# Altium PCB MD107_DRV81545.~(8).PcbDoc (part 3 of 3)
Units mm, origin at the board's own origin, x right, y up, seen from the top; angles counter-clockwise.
Board outline 152.45 x 74.46 mm, 4 copper layers (Top Layer, Mid-Layer 1, Mid-Layer 2, Bottom Layer), stack 2.355 mm thick; 223 components, 122 nets, 703 pads, 225 vias.
Unrouted connection lines stored in the file: 85.

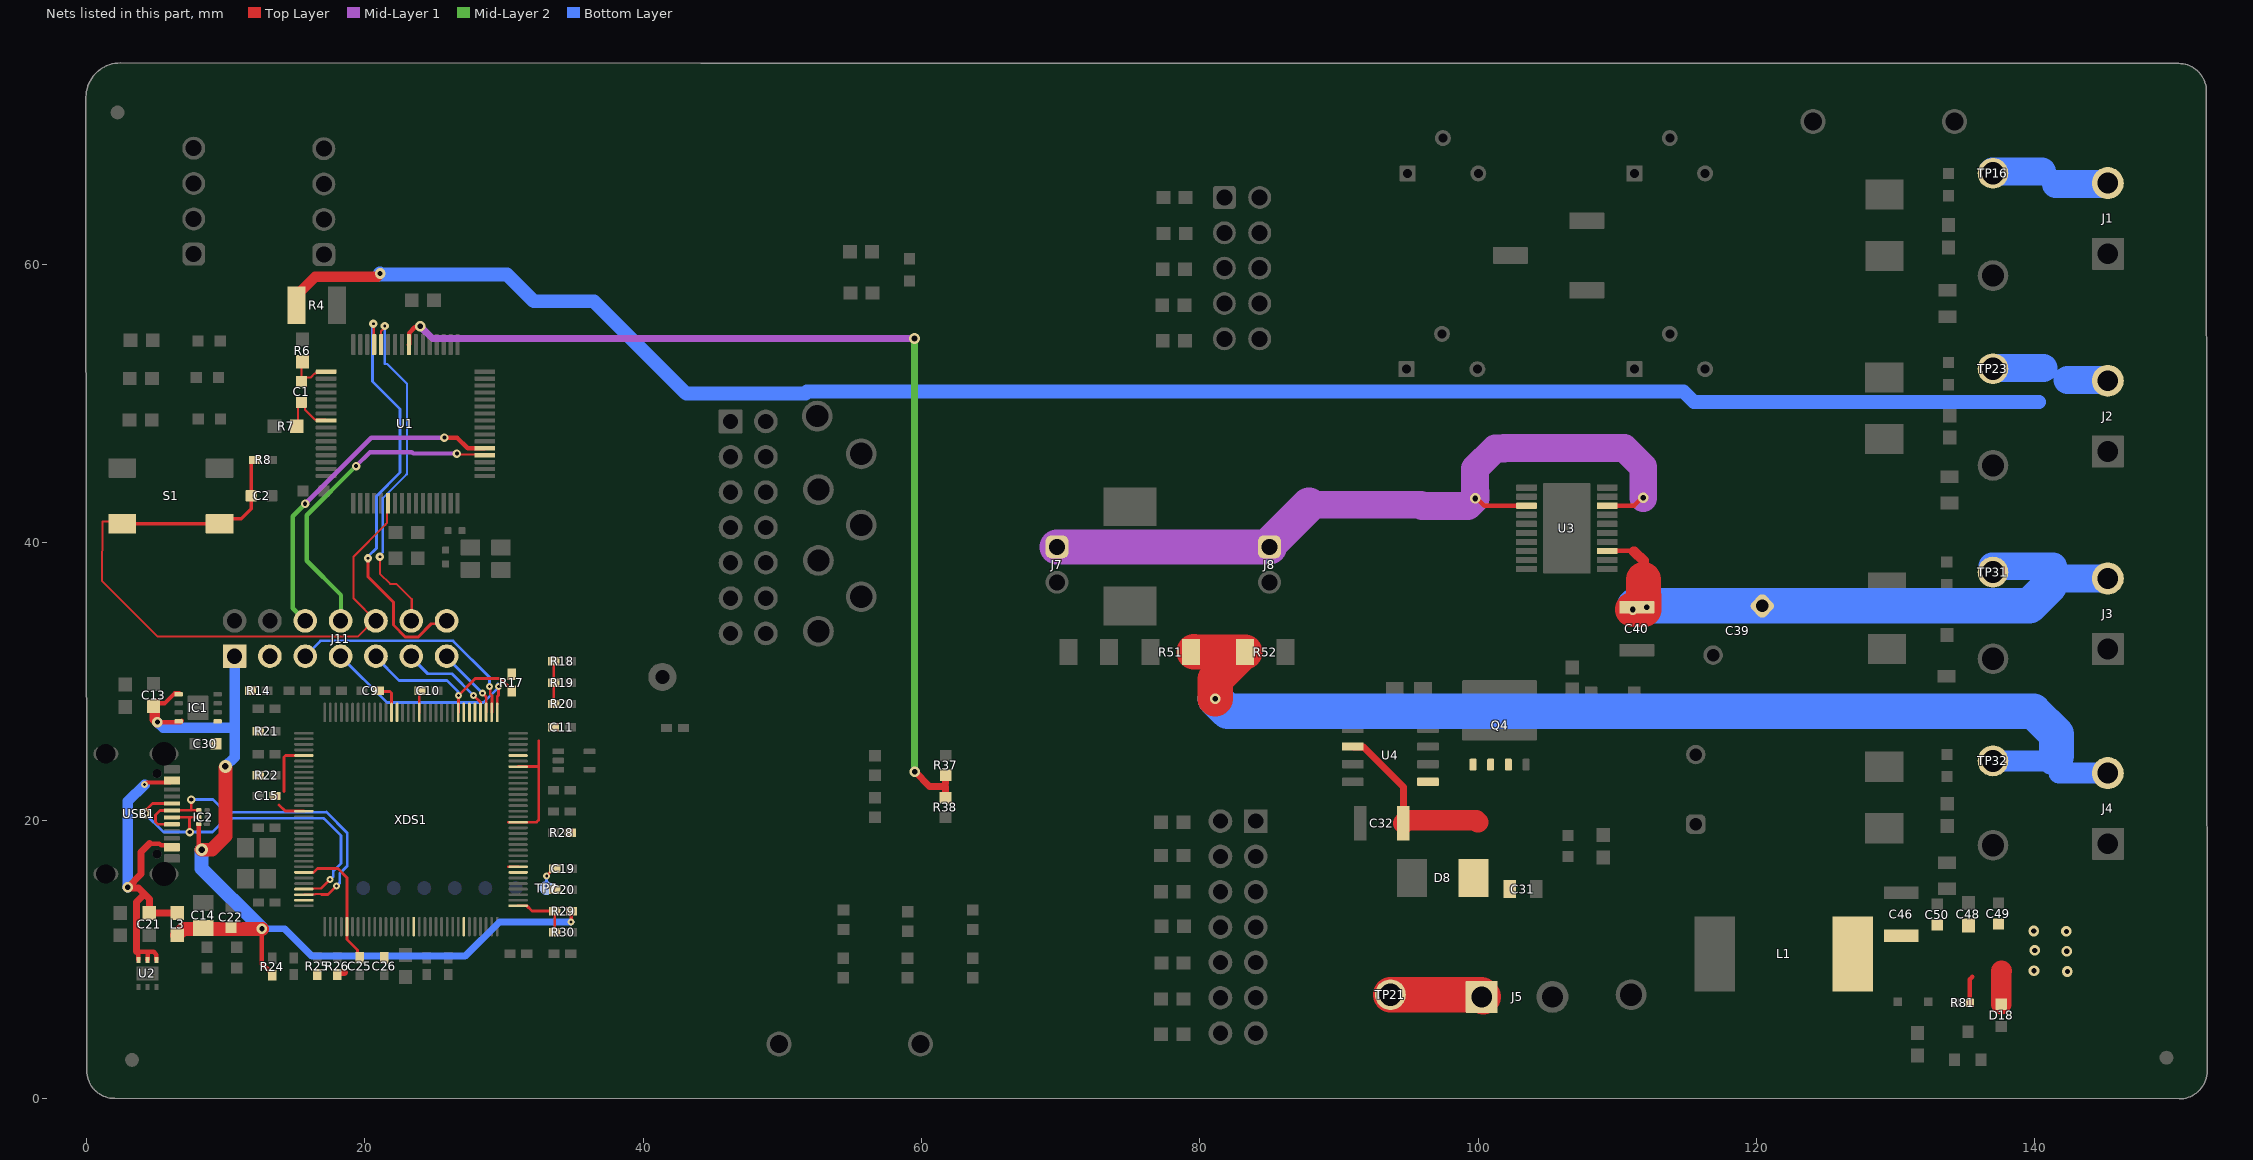
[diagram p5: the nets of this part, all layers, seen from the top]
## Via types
v1: diameter 0.762, hole 0.406, Top Layer to Bottom Layer, tented both sides, 64 vias
v2: diameter 0.508, hole 0.203, Top Layer to Bottom Layer, tented both sides, 46 vias
v3: diameter 0.5, hole 0.2, Top Layer to Bottom Layer, tented both sides, 38 vias
v4: diameter 0.762, hole 0.356, Top Layer to Bottom Layer, tented both sides, 17 vias
v5: diameter 0.61, hole 0.2, Top Layer to Bottom Layer, tented both sides, 11 vias
v6: diameter 0.762, hole 0.381, Top Layer to Bottom Layer, tented both sides, 10 vias
v7: diameter 0.61, hole 0.305, Top Layer to Bottom Layer, tented both sides, 9 vias
v8: diameter 0.711, hole 0.356, Top Layer to Bottom Layer, tented both sides, 9 vias
v9: diameter 0.61, hole 0.203, Top Layer to Bottom Layer, tented both sides, 6 vias
v10: diameter 0.5, hole 0.2, Top Layer to Bottom Layer, 6 vias
v11: diameter 0.61, hole 0.3, Top Layer to Bottom Layer, tented both sides, 4 vias
v12: diameter 0.762, hole 0.4, Top Layer to Bottom Layer, tented both sides, 2 vias
v13: diameter 0.914, hole 0.465, Top Layer to Bottom Layer, tented both sides, 2 vias
v14: diameter 0.864, hole 0.406, Top Layer to Bottom Layer, tented both sides, 1 vias

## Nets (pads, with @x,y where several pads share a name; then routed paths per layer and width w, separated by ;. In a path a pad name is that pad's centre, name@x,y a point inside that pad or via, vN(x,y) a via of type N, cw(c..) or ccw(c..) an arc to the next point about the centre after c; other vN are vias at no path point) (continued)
REV_ID2: R37.2 R38.1 U1.8 | length 72.9
  Top Layer w0.326: U1.8@23.162,54.214 23.175,54.227 23.175,55.044 23.581,55.449 23.881,55.449 v1(23.964,55.533)
  Top Layer w0.5: v1(59.523,23.519) 60.576,22.467 61.731,22.467 61.731,21.714 R38.1@61.717,21.7 ; 61.731,22.66 61.731,23.256 R37.2@61.738,23.264
  Mid-Layer 1 w0.5: v1(23.964,55.533) 24.845,54.653 v1(59.496,54.653)
  Mid-Layer 2 w0.5: v1(59.496,54.653) 59.496,23.547 v1(59.523,23.519)
RST: C2.1 J11.10 R8.1 S1.1 S1.2 U1.38 | length 50.8
  Top Layer w0.15: 1.125,41.504 1.092,37.249 5.112,33.229 19.48,33.229 20.61,34.359 J11.10@20.788,34.359 ; J11.10@20.788,34.359 19.177,35.971 19.177,38.972 21.468,41.263 21.468,41.283 21.59,41.405 21.59,42.518 U1.38@21.662,42.59
  Top Layer w0.152: 1.125,41.504 S1.2@2.536,41.504
  Top Layer w0.25: S1.2@2.553,41.342 S1.1@9.461,41.342 ; S1.1@9.553,41.342 9.9,41.689 11.107,41.689 11.841,42.423 C2.1@11.841,43.351 ; C2.1@11.824,43.351 11.824,45.803 R8.1@12.048,46.027 ; R8.1@12.015,46.041 R8.1@12.018,46.038
SWCLK: J11.14 U1.13 | length 30.4
  Top Layer w0.203: v5(20.217,38.862) 20.217,37.525 22.044,35.699 22.044,34.051 22.892,33.203 23.825,33.203 24.768,34.147 25.656,34.147 J11.14@25.868,34.359 ; v5(20.607,55.718) 20.635,55.691 20.635,54.241 U1.13@20.662,54.214
  Bottom Layer w0.203: v5(20.217,38.862) 20.217,38.972 20.818,39.573 20.818,43.312 22.52,45.014 22.52,49.579 20.539,51.561 20.539,55.65 v5(20.607,55.718)
SWDIO: J11.12 U1.12 | length 25.5
  Top Layer w0.152: v5(21.073,38.972) 21.073,37.752 21.805,37.02 22.25,37.02 23.358,35.912 23.358,34.389 J11.12@23.328,34.359 ; U1.12@21.162,54.214 21.164,54.216 21.164,55.193 21.426,55.455 v5(21.426,55.551)
  Bottom Layer w0.152: v5(21.073,38.972) 21.073,39.089 21.275,39.29 21.275,43.172 22.967,44.865 23.018,44.865 23.018,51.401 21.599,52.821 21.426,52.821 v5(21.426,55.551)
UART1_RX: J11.6 U1.53 | length 24.4
  Top Layer w0.326: v11(25.715,47.527) 26.617,47.527 27.38,46.764 U1.53@28.612,46.764
  Mid-Layer 1 w0.326: v11(15.701,42.782) 15.731,42.812 15.738,42.812 20.454,47.527 v11(25.715,47.527)
  Mid-Layer 2 w0.326: v11(15.701,42.782) 14.806,41.887 14.806,35.262 J11.6@15.708,34.359
UART1_TX: J11.8 U1.52 | length 23.4
  Top Layer w0.152: v7(26.612,46.386) 26.673,46.325 28.551,46.325 U1.52@28.612,46.264
  Mid-Layer 1 w0.32: v11(19.358,45.484) 20.361,46.487 23.376,46.487 23.477,46.386 v7(26.612,46.386)
  Mid-Layer 2 w0.32: J11.8@18.248,34.359 18.278,34.389 18.278,36.214 15.814,38.678 15.814,41.94 v11(19.358,45.484)
USB_5V: C21.1 L3.1 U2.4 U2.5 U2.6 USB1.A4-B9 USB1.A9-B4 | length 27.7
  Top Layer w0.305: v2(4.164,22.594) 4.314,22.744 5.983,22.744 USB1.A4-B9@6.122,22.884
  Top Layer w0.326: 3.642,10.595 3.652,10.585 ; U2.4@3.714,9.989 3.714,10.523 3.652,10.585 ; 4.344,10.565 4.812,10.565 5.003,10.374 5.003,10 U2.6@5.014,9.989 ; 4.344,10.585 3.652,10.585 ; U2.5@4.364,9.989 4.375,10 4.375,10.484 ; 4.521,18.351 5.229,18.351 5.359,18.221 5.985,18.221 USB1.A9-B4@6.122,18.084
  Top Layer w0.5: 3.567,10.595 3.567,14.148 4.142,14.723 ; 4.521,18.351 3.917,17.747 3.917,16.164 v6(2.959,15.206) 3.009,15.155 3.709,15.155 4.142,14.723 ; L3.1@6.504,13.362 C21.1@4.502,13.362 4.502,14.363 4.142,14.723
  Bottom Layer w0.75: v6(2.959,15.206) 2.959,21.389 v2(4.164,22.594)
VBAT: C31.2 C32.2 D8.2 J5.1 Q4.1 Q4.2 Q4.3 TP21.1 U4.2 U4.5 | length 19.7
  Top Layer w0.5: U4.2@91.001,25.327 91.051,25.277 91.776,25.277 94.638,22.415 C32.2@94.638,19.862 ; U4.5@96.401,22.787 U4.5@96.451,22.737
  Top Layer w1.5: C32.2@94.638,19.816 94.847,20.025 99.854,20.025 99.995,19.884
  Top Layer w2.54: TP21.1@93.707,7.491 100.23,7.491 J5.1@100.382,7.338
VBUS_DETECT: R29.2 R30.2 XDS1.1 | length 4.3
  Top Layer w0.203: XDS1.1@31.007,13.88 31.623,13.88 32.004,13.499 R29.2@33.644,13.499 R30.2@33.644,11.976
VCLAMP: J7.1 J8.1 U3.3 U3.18 | length 56.2
  Top Layer w0.326: v1@99.775,43.099 99.985,43.099 100.452,42.632 U3.3@103.485,42.632 ; U3.18@109.285,42.632 111.213,42.632 111.804,43.223 v1@111.981,43.223 ; v1@111.868,43.193 v1(111.875,43.2)
  Mid-Layer 1 w2: J8.1@85.011,39.671 85.285,39.945 J8.1@85.285,40.128 ; 87.856,42.699 95.89,42.699 95.972,42.617 99.269,42.617 v1(99.808,43.157) 99.808,43.62 99.781,43.648 99.781,45.305 101.232,46.756 101.858,46.756 101.885,46.783 110.503,46.783 111.875,45.411 v1(111.875,43.2)
  Mid-Layer 1 w2.5: J7.1@69.737,39.673 J8.1@85.008,39.673 ; J8.1@85.285,40.128 87.856,42.699
VM: C39.1 C40.2 C46.2 C48.2 C49.2 C50.2 D18.2 J1.2 J2.2 J3.2 J4.2 L1.2 R4.2 R51.2 R52.2 R81.2 TP16.1 TP23.1 TP31.1 TP32.1 U3.13 | length 271.6
  Top Layer w0.326: U3.13@109.285,39.382 111.16,39.382 111.201,39.341 ; C40.2@111.989,35.54 C40.2@112.132,35.397 ; R81.2@135.353,6.898 135.353,8.586 135.53,8.764
  Top Layer w0.75: R4.2@14.951,57.317 14.951,57.617 16.42,59.086 v4@20.874,59.086 ; 111.201,39.341 111.241,39.341 111.897,38.686 111.897,37.325
  Top Layer w1.5: D18.2@137.603,6.804 137.603,9.178 137.612,9.187
  Top Layer w2.54: R51.2@79.585,32.14 79.605,32.119 R52.2@83.252,32.119 ; v1(81.116,28.754) 81.116,30.151 R52.2@82.917,31.952 ; v1(111.126,35.173) 111.904,35.173 111.904,35.176 111.903,35.343 111.903,35.348 111.897,37.325
  Mid-Layer 2 w1.5: TP32.1@136.938,24.289 TP32.1@137.012,24.289 TP32.1@137.13,24.289
  Bottom Layer w1: v4(21.094,59.322) 21.158,59.258 30.221,59.258 32.152,57.328 36.475,57.328 43.091,50.712 51.656,50.712 51.778,50.834 114.766,50.834 115.514,50.085 140.304,50.085
  Bottom Layer w1.5: TP32.1@137.012,24.289 140.922,24.289 141.136,24.075 ; 141.758,23.416 J4.2@145.263,23.416
  Bottom Layer w2: TP31.1@136.957,38.279 141.317,38.279 ; TP23.1@136.997,52.527 140.633,52.527 ; TP16.1@136.997,66.655 140.538,66.655 ; 141.521,65.764 J1.2@145.206,65.764 ; 142.17,37.406 J3.2@145.263,37.406 ; 142.37,51.671 J2.2@145.206,51.671
  Bottom Layer w2.54: v1(81.116,28.754) 82.014,27.856 139.924,27.856 141.571,26.21 141.571,24.67 ; v1@111.272,35.449 139.395,35.449 ; 139.619,35.429 141.071,36.881
  other v1: 112.13,35.349
  other v6: 142.362,9.159 139.962,9.2 142.321,10.619 140.013,10.67 142.29,12.039 139.931,12.069
VREF_N: C1.1 R6.2 U1.17 | length 3.3
  Top Layer w0.152: R6.2@15.391,52.814 15.428,52.776 C1.1@15.428,51.564 15.71,51.846 16.099,51.846 16.396,52.143 16.491,52.143 16.612,52.264 U1.17@17.212,52.264
VREF_P: C1.2 R7.2 U1.24 | length 3.9
  Top Layer w0.152: R7.2@15.19,48.764 15.19,49.826 C1.2@15.428,50.064 15.69,49.802 15.69,49.525 16.377,48.838 17.138,48.838 U1.24@17.212,48.764
XDS_ID: XDS1.95
XDS_RESET_OUT: J11.9 R17.1 XDS1.40 | length 13.3
  Top Layer w0.203: v2(26.717,29.002) 27.93,30.215 29.749,30.215 30.545,29.419 R17.1@30.545,29.319 ; XDS1.40@26.718,27.789 v2@26.718,29.002
  Bottom Layer w0.203: J11.9@20.788,31.819 20.788,31.742 22.457,30.074 25.891,30.074 26.678,29.286 26.678,29.041 v2(26.717,29.002)
XDS_RXD: J11.7 XDS1.33 | length 14.8
  Top Layer w0.203: XDS1.33@29.507,28.379 29.507,28.912 29.607,29.011 v2(29.607,29.631)
  Bottom Layer w0.203: J11.7@18.248,31.819 21.573,28.494 28.528,28.494 29.607,29.573 v2(29.607,29.631) 29.548,29.689 v2@29.548,29.841
XDS_TCK_SWDCLK: J11.13 XDS1.35 | length 5.2
  Top Layer w0.203: v2(28.45,29.16) 28.719,28.891 XDS1.35@28.719,27.788
  Bottom Layer w0.203: J11.13@25.868,31.819 25.868,31.742 v2(28.45,29.16)
XDS_TDI: XDS1.38
XDS_TDO_SWO: XDS1.37
XDS_TMS_SWDIO: J11.11 XDS1.36 | length 7.1
  Top Layer w0.203: v2(27.805,29.002) 28.317,28.49 28.317,27.79 XDS1.36@28.319,27.788
  Bottom Layer w0.203: J11.11@23.328,31.819 23.328,31.742 24.51,30.56 26.248,30.56 v2(27.805,29.002)
XDS_TXD: J11.5 XDS1.34 | length 17.4
  Top Layer w0.203: v2(28.946,29.631) 29.005,29.572 29.005,29.109 29.119,28.994 XDS1.34@29.119,27.788
  Bottom Layer w0.203: J11.5@15.708,31.819 16.812,32.923 26.326,32.923 28.946,30.303 v2(28.946,29.631)
XDS_USB_D_N: IC2.5 USB1.A7 USB1.B7 XDS1.93 | length 26.6
  Top Layer w0.152: XDS1.93@15.607,15.087 16.215,15.087 16.253,15.124 16.842,15.124 16.868,15.15
  Top Layer w0.203: v6(4.164,20.535) 4.164,20.658 4.74,21.234 USB1.B7@6.122,21.234 ; USB1.A7@6.122,20.234 6.131,20.242 7.457,20.242 ; v7(7.399,19.179) 7.386,19.192 7.386,20.171 7.457,20.242 ; IC2.5@8.061,20.25 8.053,20.242 7.457,20.242 ; 16.868,15.15 16.878,15.15 v3(17.491,15.763)
  Bottom Layer w0.203: v6(4.164,20.535) 5.52,19.179 v7(7.399,19.179) 9.029,19.179 9.981,20.131 ; 9.982,20.179 17.043,20.157 18.271,18.929 18.271,16.927 17.726,16.382 17.726,15.998 v3(17.491,15.763)
XDS_USB_D_P: IC2.4 USB1.A6 USB1.B6 XDS1.94 | length 24.8
  Top Layer w0.152: XDS1.94@15.607,14.68 16.384,14.68 16.421,14.718 16.842,14.718 16.868,14.693
  Top Layer w0.203: USB1.B6@6.122,19.734 5.114,19.734 4.935,19.913 4.935,20.396 5.273,20.734 USB1.A6@6.122,20.734 6.131,20.742 7.444,20.742 ; v7(7.52,21.515) 7.52,20.818 7.444,20.742 ; IC2.4@8.061,20.75 8.053,20.742 7.444,20.742 ; 16.868,14.693 17.343,14.693 v3(17.952,15.302)
  Bottom Layer w0.203: v7(7.52,21.515) 9.084,21.515 9.963,20.636 ; 9.963,20.588 17.232,20.614 18.728,19.118 18.728,16.738 18.183,16.193 18.183,15.532 v3(17.952,15.302)
XDS_VBUS: C13.1 C14.1 C22.1 IC1.5 IC1.8 IC2.6 J11.1 L3.2 R24.1 R29.1 | length 70.5
  Top Layer w0.254: v2(34.814,12.714) 34.814,13.469 R29.1@34.844,13.499
  Top Layer w0.326: C13.1@4.801,28.42 5.59,28.42 6.313,29.142 IC1.5@6.641,29.142 ; v4(5.083,27.082) 6.744,27.082 IC1.8@6.846,27.184 ; IC2.6@8.061,19.75 8.061,18.188 8.235,18.014 v13@8.235,17.975 ; v6(12.595,12.231) 12.595,12.212 12.595,9.695 12.909,9.381 12.955,9.381 13.195,9.141 R24.1@13.195,8.794
  Top Layer w0.508: J11.1@10.599,31.79 J11.1@10.628,31.819
  Top Layer w0.75: C13.1@4.876,28.395 4.876,27.288 v4(5.083,27.082)
  Top Layer w1: L3.2@6.504,11.762 6.951,12.21 7.249,12.21 7.251,12.212 v6@12.595,12.212 ; v13(8.263,17.91) 8.993,17.91 9.964,18.88 v13@9.964,23.803
  Bottom Layer w0.5: v6(12.595,12.231) 14.217,12.231 16.193,10.255 27.198,10.255 29.657,12.714 v2(34.814,12.714)
  Bottom Layer w0.75: v4(5.083,27.082) 5.503,26.661 10.628,26.661 ; v13(9.972,23.899) 10.628,24.554 10.628,26.661 ; J11.1@10.628,31.819 10.628,26.661
  Bottom Layer w1: v13(8.263,17.91) 8.263,16.563 v6(12.595,12.231)
XDS_VCC: C9.1 C10.1 C11.1 C15.1 C19.1 C20.1 C25.1 C26.1 C30.2 IC1.1 J11.3 R14.2 R17.2 R18.2 R19.2 R20.2 R21.2 R22.2 R25.1 R26.1 R28.2 TP7.1 XDS1.7 XDS1.8 XDS1.16 XDS1.26 XDS1.28 XDS1.39 XDS1.47 XDS1.51 XDS1.52 XDS1.69 XDS1.79 XDS1.90 XDS1.101 XDS1.113 XDS1.122 | length 35.6
  Top Layer w0.203: C15.1@13.529,21.772 C15.1@13.629,21.772 ; 13.827,21.128 14.267,20.688 XDS1.79@15.619,20.688 ; C15.1@13.827,21.574 C15.1@13.629,21.772 ; C15.1@13.827,21.971 C15.1@13.629,21.772 ; 14.183,22.09 14.183,24.561 14.302,24.68 XDS1.69@15.009,24.68 ; XDS1.90@15.607,16.28 16.308,16.28 16.577,16.55 18.05,16.55 18.707,15.892 XDS1.101@18.707,12.38 18.707,11.447 19.459,10.696 19.459,10.328 C25.1@19.637,10.149 ; C9.1@20.942,29.482 21.14,29.283 21.798,29.283 21.917,29.164 21.917,27.79 XDS1.52@21.919,27.788 ; XDS1.47@23.907,27.78 23.907,29.287 C10.1@23.957,29.336 ; XDS1.8@30.317,16.69 31.017,16.69 XDS1.8@31.019,16.688 ; XDS1.16@30.317,19.886 31.613,19.886 31.617,19.89 32.336,19.89 32.489,20.043 32.489,25.743 ; R17.2@30.418,30.392 R17.2@30.545,30.519 ; XDS1.7@31.017,16.286 XDS1.7@31.019,16.288 ; XDS1.26@31.019,23.888 31.615,23.888 31.617,23.89 32.489,23.89 ; v2(33.061,16.016) 33.061,16.062 33.544,16.545 C19.1@33.644,16.545 ; C11.1@33.456,26.709 C11.1@33.556,26.709 ; R18.2@33.568,31.452 R19.2@33.568,29.919 R20.2@33.568,28.386 R20.2@33.668,28.386
  Top Layer w0.508: R26.1@18.011,8.949 18.011,9.049 18.057,9.095 18.509,9.095 ; C25.1@19.637,10.049 C25.1@19.637,10.149
  Bottom Layer w0.203: TP7.1@33.036,15.153 33.048,15.165 33.048,16.004 v2(33.061,16.016)
pads on no net: FID1.1 FID2.1 FID3.1 IC1.2 IC1.3 IC1.6 IC1.7 IC2.1 IC2.2 IC3.2 IC3.4 IC3.5 Q4.9@99.171,26.018 Q4.9@100.213,26.313 Q4.9@100.213,27.463 Q4.9@100.213,28.613 Q4.9@101.543,26.313 Q4.9@101.543,27.463 Q4.9@101.543,27.598 Q4.9@101.543,28.613 Q4.9@102.873,26.313 Q4.9@102.873,27.463 Q4.9@102.873,28.613 Q4.9@103.916,26.018 SH-J1.0 SH-J2.0 SH-J3.0 SH-J4.0 SH-J5.0 SH-J6.0 SH-J7.0 SH-J8.0 SH-J10.0 SH-J11.0 SH-J12.0 SH-J14.0 SH-J15.0 SH-J16.0 SH-J17.0 SH-J18.0 SH-J19.0 SH-J20.0 U1.2 U1.3 U1.5 U1.6 U1.7 U1.18 U1.20 U1.21 U1.22 U1.25 U1.28 U1.29 U1.31 U1.39 U1.42 U1.44 U1.47 U1.48 U1.49 U1.50 U1.51 U1.55 U1.56 U1.57 U1.61 U2.7@3.914,9.014 U2.7@4.814,9.014 U3.9 U4.3 U4.7 USB1. USB1.A8 USB1.B8 XDS1.2 XDS1.5 XDS1.6 XDS1.11 XDS1.12 XDS1.13 XDS1.14 XDS1.15 XDS1.18 XDS1.19 XDS1.20 XDS1.21 XDS1.22 XDS1.23 XDS1.24 XDS1.25 XDS1.27 XDS1.29 XDS1.30 XDS1.31 XDS1.32 XDS1.41 XDS1.43 XDS1.44 XDS1.45 XDS1.46 XDS1.49 XDS1.50 XDS1.53 XDS1.54 XDS1.56 XDS1.57 XDS1.65 XDS1.67 XDS1.71 XDS1.72 XDS1.73 XDS1.74 XDS1.75 XDS1.76 XDS1.77 XDS1.78 XDS1.81 XDS1.82 XDS1.83 XDS1.84 XDS1.85 XDS1.86 XDS1.91 XDS1.92 XDS1.102 XDS1.103 XDS1.104 XDS1.105 XDS1.106 XDS1.107 XDS1.108 XDS1.109 XDS1.110 XDS1.111 XDS1.112 XDS1.116 XDS1.117 XDS1.118 XDS1.119 XDS1.121 XDS1.123 XDS1.124 XDS1.125 XDS1.126 XDS1.127 XDS1.128
copper on no net:
  other v2: 16.754,14.111 16.729,15.864

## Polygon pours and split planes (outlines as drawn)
OUT4 on Top Layer "TOP_LAYER_OUT4_P395" (solid, remove dead copper, pour order 395): 150.892,21.051 150.844,21.003 136.256,21.003 135.775,20.522 131.506,20.515 127.583,24.987 114.953,40.171 112.115,40.171 112.138,39.61 117.376,33.006 125.261,19.989 125.261,16.966 127.583,15.9 150.844,15.9 150.844,20.859 150.892,20.907
VBAT on Top Layer "TOP_LAYER_VBAT_P436" (solid, remove dead copper, pour order 436): 98.273,22.346 95.819,22.337 95.723,23.252 99.062,23.173 98.994,24.792 102.748,24.792 102.56,2.491 97.407,2.491
PI_IN on Top Layer "TOP_LAYER_PI_IN_P392" (solid, remove dead copper, pour order 392): 105.636,26.292 95.427,26.292 95.427,30.224 105.601,30.224 109.405,30.224 109.405,21.892 116.47,21.914 119.476,19.78 119.476,6.829 118.763,6.116 118.721,6.158 114.861,6.158 114.861,17.232 113.561,18.532 105.601,18.532
GND on Top Layer "TOP_LAYER_GND_P439" (solid, remove dead copper, pour order 439): -0.259,73.926 151.6,73.926 151.6,-0.622 151.181,-1.04 150.881,-0.74 -0.8,-0.74 -0.8,74.576
XDS_VCC on Top Layer "TOP_LAYER_XDS_VCC_P437" (solid, remove dead copper, pour order 437): 8.504,2.889 9.526,1.945 10.085,1.945 33.378,1.945 34.8,3.367 34.8,8.487 38.242,8.487 39.32,9.565 39.218,9.666 39.218,32.399 8.504,32.399
no net on Top Layer "TOP_LAYER_NONET_P435" (solid, remove dead copper, pour order 435): 14.274,37.249 14.417,37.392 14.417,40.937 12.229,40.937 11.507,40.214 11.507,37.249
3V3_MCU on Top Layer "TOP_LAYER_3V3_MCU_P433" (solid, remove dead copper, pour order 433): 8.888,47.733 8.866,47.754 8.866,49.495 10.857,49.495 10.857,48.24 10.349,47.733 8.871,47.733
OUT1 on Top Layer "TOP_LAYER_OUT1_P432" (solid, remove dead copper, pour order 432): 150.698,62.503 150.65,62.455 136.062,62.455 135.581,61.974 125.518,61.891 123.833,60.207 123.826,57.536 123.833,57.444 123.834,57.352 123.575,55.269 113.597,45.022 113.649,43.479 112.558,42.264 113.162,41.982 114.162,43.068 115.448,42.991 126.689,54.157 126.735,55.255 126.82,57.257 150.65,57.352 150.65,62.311 150.698,62.359
OUT2 on Top Layer "TOP_LAYER_OUT2_P430" (solid, remove dead copper, pour order 430): 150.658,49.041 150.61,48.993 136.022,48.993 135.541,48.511 125.265,48.427 117.888,43.74 115.07,41.725 112.987,41.75 113.042,41.118 118.078,41.064 119.099,41.346 121.619,42.528 123.602,43.89 123.794,43.89 150.61,43.89 150.61,48.848 150.658,48.896
OUT3 on Top Layer "TOP_LAYER_OUT3_P429" (solid, remove dead copper, pour order 429): 150.708,34.792 150.66,34.744 136.073,34.744 135.591,34.262 128.571,34.368 127.275,35.381 125.141,37.798 121.541,41.115 116.25,40.906 111.776,40.906 111.776,40.335 117.557,40.297 124.447,33.273 123.843,32.495 123.843,30.557 123.836,30.564 125.141,29.641 150.66,29.641 150.66,34.599 150.708,34.647
VM on Top Layer "TOP_LAYER_VM_P389" (solid, remove dead copper, pour order 389): 125.526,12.992 125.705,12.992 144.653,12.992 144.653,7.918 144.344,7.609 125.364,7.609 125.364,12.911 125.526,13.073 125.543,13.073
no net on Top Layer "TOP_LAYER_NONET_P388" (solid, remove dead copper, pour order 388): 129.228,15.345 129.177,15.345 138.366,15.345 138.366,13.448 138.211,13.293 138.071,13.433 129.099,13.433 129.099,15.33 129.084,15.345 129.255,15.345
GND on Mid-Layer 2 "MID-LAYER_2_GND_P438" (solid, remove dead copper, pour order 438): 0.07,0.445 0.07,74.499 152.47,74.499 152.47,0.445
VM on Mid-Layer 2 "MID-LAYER_2_VM_P427" (solid, remove dead copper, pour order 427): 127.906,23.14 127.88,23.114 120.8,23.114 120.8,26.072 129.193,26.072 129.392,26.272 129.392,23.14 127.927,23.14 127.906,23.161
VM on Bottom Layer "BOTTOM_LAYER_VM_P408" (solid, remove dead copper, pour order 408): 139.339,68.647 139.368,68.618 143.517,68.618 143.517,7.794 143.344,7.621 143.315,7.65 139.396,7.65 139.396,68.561 139.368,68.589
GND on Bottom Layer "BOTTOM_LAYER_GND_P413" (solid, remove dead copper, pour order 413): -0.669,75.235 151.517,75.235 151.731,75.449 151.731,-0.42 -0.669,-0.42
3V3_MCU on Mid-Layer 1 "MID-LAYER_1_3V3_MCU_P401" (solid, remove dead copper, pour order 401): 42.813,33.329 44.447,33.328 44.474,47.955 47.363,47.926 47.428,50.064 42.034,49.992 42.034,36.688 36.647,36.688 31.629,36.688 14.64,36.688 14.736,48.47 14.64,48.47 12.881,49.932 0.917,49.908 0.917,36.335 3.923,33.329
GND on Mid-Layer 1 "MID-LAYER_1_GND_P421" (solid, remove dead copper, pour order 421): -0.84,-0.844 -0.84,73.832 151.56,73.832 151.56,-0.844

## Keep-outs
Keep-Out Layer:
  lines w0.508: -0.129,74.422 152.271,74.422 152.4,0 0,0 0,15.58 0,23.855 0,74.422
  text ".Layer_Name" at 14.316,-21.806 h1.52

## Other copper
Top Layer:
  region net XDS_VCC: 27.203,11.032 27.025,11.032 27.025,15.094 27.097,15.094 27.203,15.094 27.203,12.613
  region net XDS_VCC: 29.073,19.801 29.657,19.801 30.851,19.801 30.851,19.953 30.826,19.979 29.073,19.979
  region net XDS_VCC: 31.004,24.576 29.073,24.576 29.073,24.779 31.004,24.779
  region net XDS_VCC: 31.004,23.789 29.073,23.789 29.073,23.992 29.124,23.992 31.004,23.992
  region net XDS_VCC: 29.073,16.194 29.632,16.194 32.35,16.194 32.35,16.88 32.35,16.778 32.197,16.778 29.073,16.778
  pour cut-out: 12.499,9.358 16.876,9.358 16.876,13.852 12.499,13.852
  pour cut-out: 29.505,11.241 18.812,11.241 18.812,13.349 18.989,13.527 29.48,13.527 29.505,13.502
  pour cut-out: 16.754,15.915 16.754,23.89 14.468,23.89 14.468,16.245 14.798,15.915
  pour cut-out: 30.318,13.832 32.098,13.832 32.173,13.908 32.172,13.909 32.172,26.634 31.994,26.811 30.191,26.811 29.845,26.466 29.845,14.152
  region net XDS_VCC: 23.612,11.976 23.612,14.01 23.409,14.01 23.409,11.976
  region net XDS_VCC: 15.535,20.588 15.535,20.792 18.151,20.792 18.151,20.614 18.151,20.588
  pour cut-out: 10.504,16.792 11.891,16.792 11.677,17.006 11.677,17.186 10.504,17.186
  region net XDS_VCC: 23.815,27.853 23.815,25.44 23.993,25.44 23.993,27.853
  region net XDS_VCC: 27.016,27.853 27.016,25.287 27.194,25.287 27.194,27.853
  region net XDS_VCC: 21.809,25.44 22.418,25.44 22.418,29.631 21.809,29.631
  pour cut-out: 30.038,28.386 30.038,26.946 29.691,26.634 20.945,26.634 20.945,28.97 29.708,28.97
  text ".Layer_Name" at 14.316,-21.806 h1.52
Mid-Layer 1:
  pour cut-out: 10.252,13.832 10.252,20.106 13.681,20.106 13.681,18.805 14.69,18.805 14.9,18.594 14.9,15.407 14.671,15.178 13.681,15.178 13.681,13.832
Mid-Layer 2:
  pour cut-out: 10.252,13.832 13.655,13.832 13.681,13.857 13.681,15.178 14.671,15.178 14.9,15.407 14.9,18.594 14.69,18.805 13.681,18.805 13.681,20.106 10.252,20.106
Bottom Layer:
  text ".Layer_Name" at 14.316,-21.806 h1.52

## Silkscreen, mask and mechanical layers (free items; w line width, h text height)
Top Overlay:
  drawing of 1228 lines, arcs and shapes, not listed
  text "GND" at 120.46,71.466 h2.7
  text "AUXILARY PINOUTS" at 3.862,71.077 h1.52
  text "DRV81545PWP" at 49.539,70.559 h3
  text "PWM IN2" at 94.55,70.214 h1.5
  text "PWM IN3" at 110.865,70.125 h1.5
  text "MSPM0" at 38.296,69.829 h3
  text "VM" at 135.928,68.501 h1.78
  text "Cut Off Delay" at 67.335,68.286 h1.65
  text "PB24" at 9.817,67.655 h1.5
  text "PB13" at 20.039,67.611 h1.5
  text "(OUT1)" at 126.23,66.908 h1.52
  text "HW" at 104.108,66.225 h2
  text "PB25" at 9.817,65.276 h1.5
  text "PB12" at 20.039,65.231 h1.5
  text "DISABLED" at 67.674,64.151 h1.52
  text "nFAULT LED" at 52.771,64.06 h1.52
  text "DRV81545EVM" at 27.392,63.09 h3.05
  text "PA0" at 9.817,62.539 h1.5
  text "PB11" at 20.039,62.495 h1.5
  text "0.5 ms" at 67.678,61.736 h1.52
  text "OUT1" at 135.106,61.095 h1.78
  text "0%" at 99.082,60.734 h1.5
  text "100%" at 110.11,60.74 h1.5
  text "0%" at 115.549,60.71 h1.5
  text "100%" at 93.55,60.621 h1.5
  text "PA1" at 9.817,60.001 h1.5
  text "PB10" at 20.039,59.956 h1.5
  text "MD107.PCB_Rev" at 31.077,59.765 h2.75
  text "1 ms" at 67.678,58.839 h1.52
  text "LED STATUS" at 1.04,56.729 h1.52
  text "1.5 ms" at 67.678,56.079 h1.52
  text "PWM IN1" at 94.46,56.044 h1.5
  text "PWM IN4" at 110.731,55.999 h1.5
  text "OUT1" at 139.276,55.479 h2.54
  text "MCU_STATUS" at 2.383,55.132 h0.76
  text "VM" at 135.928,54.294 h1.78
  text "2 ms" at 67.678,53.596 h1.52
  text "GUI" at 103.39,53.217 h2
  text "(OUT2)" at 126.13,53.078 h1.52
  text "GUI_STATUS" at 2.682,52.805 h0.76
  text "3V3_STATUS" at 2.78,49.928 h0.76
  text "DECAY MODES" at 67.524,48.355 h1.52
  text "3V3" at 57.869,47.981 h2.5
  text "OUT2" at 135.379,47.433 h1.78
  text "0%" at 99.129,46.685 h1.5
  text "100%" at 93.671,46.647 h1.5
  text "100%" at 109.99,46.549 h1.5
  text "0%" at 115.519,46.529 h1.5
  text "VCLAMP" at 77.51,45.949 h0.76
  text "nFAULT" at 57.601,45.572 h2.5
  text "FAST" at 67.767,45.487 h2.54
  text "SLOW" at 82.803,45.487 h2.54
  text "IN1" at 57.669,42.973 h2.5
  text "OUT2" at 139.276,41.357 h2.54
  text "IN2" at 57.705,40.267 h2.5
  text "VM" at 135.867,39.725 h1.78
  text "(OUT3)" at 126.04,38.042 h1.52
  text "IN3" at 57.674,37.742 h2.5
  text "NRST" at 34.756,36.097 h2.03 r90
  text "SWDIO" at 36.799,36.097 h2.03 r90
  text "SWCLK" at 39.317,36.097 h2.03 r90
  text "RXD>>" at 16.015,35.861 h2.03 r90
  text "TXD <<" at 19.575,35.778 h2.03 r90
  text "DRV81545" at 102.274,35.385 h1.02
  text "IN4" at 57.702,34.96 h2.5
  text "Target" at 28.359,33.639 h1.14
  text "OUT3" at 135.409,33.499 h1.78
  text "GND" at 57.699,32.613 h2.5
  text "Debugger" at 27.93,31.452 h1.14
  text "GND" at 68.341,28.176 h0.76
  text "VM" at 80.163,28.104 h1
  text "OUT3" at 139.276,27.076 h2.54
  text "REVISION ID" at 52.409,26.623 h1.52
  text "VM" at 135.928,26.154 h1.78
  text "(OUT4)" at 126.08,25.317 h1.52
  text "ILIM" at 67.183,23.309 h1.52
  text "REV_ID1" at 54.661,20.224 h1.27 r90
  text "REV_ID2" at 59.648,20.151 h1.27 r90
  text "OUT4" at 135.295,20.139 h1.78
  text "3 A" at 67.245,19.166 h1.52
  text "2 A" at 67.431,16.981 h1.52
  text "DEVICE ID" at 49.868,15.225 h1.52
  text "1.5 A" at 67.481,14.567 h1.52
  text "OUT4" at 139.276,13.209 h2.54
  text "1 A" at 67.531,12.354 h1.52
  text "0.75 A" at 67.835,9.555 h1.52
  text "VM LED" at 129.267,9.534 h1.52
  text "DEV_ID2" at 57.082,8.683 h1.5 r90
  text "DEV_ID1" at 52.2,8.623 h1.5 r90
  text "DEV_ID3" at 61.699,8.645 h1.5 r90
  text "0.5 A" at 67.879,6.899 h1.52
  text "0.25 A" at 67.72,4.151 h1.52
  text "GND" at 43.436,3.238 h2.7
  text "4.5V-55V DC" at 114.798,2.24 h2.54
  text "GND" at 108.355,1.665 h3.5
  text "VM" at 90.857,1.572 h3.5
  text "VM" at 51.623,-5.086 h0.76
  text ".Layer_Name" at 22.646,-21.806 h1.52
Bottom Overlay:
  lines w0.254: 86.969,2.36 116.897,2.36 116.897,26.549 86.969,26.549 86.969,2.36
  text "VM" at 138.206,68.272 h1.5
  text "OUT1" at 140.216,61.052 h1.5
  text "VM" at 138.566,54.179 h1.5
  text "3V3" at 57.011,48.986 h1.27
  text "OUT2" at 139.501,47.362 h1.5
  text "nFAULT" at 61.917,46.006 h1.27
  text "IN1" at 56.598,43.333 h1.27
  text "IN2" at 60.037,40.811 h1.27
  text "VM" at 138.292,39.555 h1.5
  text "IN3" at 56.736,38.166 h1.27
  text "IN4" at 60.037,35.676 h1.27
  text "OUT3" at 139.446,33.342 h1.5
  text "VM" at 138.017,26.029 h1.5
  text "OUT4" at 139.336,20.256 h1.5
  text "GND" at 20.31,14.01 h1.27 r90
  text "ITMS" at 22.495,14.01 h1.27 r90
  text "ITCK" at 24.679,14.01 h1.27 r90
  text "ITDO" at 26.889,14.01 h1.27 r90
  text "ITDI" at 29.073,14.01 h1.27 r90
  text "IRSTN" at 31.308,14.01 h1.27 r90
  text "XDS_VCC" at 33.671,14.01 h1.27 r90
  text "Quick Start / 1. Connect USB, VM, GND, and Load  / 2. Open GUI at dev.ti.com/gallery / 3. In the GUI start each channel." at 116.109,8.183 h0.76
  text ".Layer_Name" at 14.316,-21.806 h1.52
Top Paste:
  text ".Layer_Name" at 14.316,-21.806 h1.52
Bottom Paste:
  text ".Layer_Name" at 14.316,-21.806 h1.52
Top Solder:
  text ".Layer_Name" at 14.316,-21.806 h1.52
  text ".Layer_Name" at 14.316,-21.806 h1.52
Bottom Solder:
  text ".Layer_Name" at 14.316,-21.806 h1.52
Drill Guide:
  text ".Layer_Name" at 14.316,-21.806 h1.52
M1 Board Outline:
  lines w0.254: 142.516,74.297 150.335,74.297 ; 142.737,74.304 2.42,74.461 ccw(c2.42,71.99) -0.051,71.99 -0.051,63.922 0,17.163 0,15.58 0,2.032 ccw(c2,2.032) 2,0.032 150.4,0 ccw(c150.4,2) 152.4,2 152.349,72.422 ; 150.36,74.336 cw(c150.36,72.336) 152.36,72.336
  text ".Layer_Name" at 14.316,-21.806 h1.52
M2 Board Dimensions:
  rectangle: -0.34,-6.985 2.835,-3.81
  rectangle: 2.835,-10.16 12.36,-6.985
  lines w0.178: -0.34,-6.985 25.06,-6.985 ; 2.835,-10.16 2.835,-3.81 ; 6.01,-10.16 6.01,-3.81 ; 12.36,-10.16 12.36,-3.81 ; 18.71,-10.16 18.71,-3.81 ; -0.34,-10.16 25.06,-10.16 25.06,-3.81 -0.34,-3.81 -0.34,-10.16
  text ".Layer_Name" at 14.316,-21.806 h1.52
M3 3D STEP Top:
  text ".Layer_Name" at 14.316,-21.806 h1.52
M4 3D STEP Bottom:
  text ".Layer_Name" at 14.316,-21.806 h1.52
M5 Assembly Top:
  lines w0.254: -7.757,-23.626 159.883,-23.626 ; -7.757,-18.462 159.934,-18.462 ; -7.757,-13.297 -7.757,-28.791 93.97,-28.791 159.934,-28.791 159.934,-13.297 -7.744,-13.297 -7.744,-28.791 32.274,-28.791 ; 54.854,-28.791 54.854,-13.297 ; 87.036,-18.462 87.036,-13.297 ; 108.372,-18.462 108.372,-13.297 ; 124.171,-28.956 124.171,-23.804
  text "COMPONENTS MARKED 'DNP' SHOULD NOT BE POPULATED." at 28.959,-8.09 h1.52
  text "ASSEMBLY VARIANT:" at 28.946,-11.024 h1.52
  text ".VariantName" at 55.261,-11.024 h1.52
  text "PCB VIEWED FROM TOP SIDE" at -6.144,-16.654 h1.52
  text "BOARD #:" at 56.759,-16.654 h1.52
  text ".PRJ_Number" at 70.615,-16.654 h1.52
  text "REV:" at 92.065,-16.654 h1.52
  text ".PCB_Rev" at 99.469,-16.654 h1.52
  text "SVN REV:" at 113.35,-16.654 h1.52
  text ".VersionControl_RevNumber" at 126.203,-16.654 h1.52
  text "TID #:" at 56.759,-21.819 h1.52
  text ".TID" at 70.615,-21.819 h1.52
  text "PLOT NAME =" at -6.144,-27.034 h1.52
  text ".plot_File_Name" at 14.316,-27.034 h1.52
  text "GENERATED    :" at 56.81,-27.034 h1.52
  text ".Print_Date" at 78.895,-27.034 h1.52
  text ".Print_Time" at 97.412,-27.034 h1.52
  text "TEXAS INSTRUMENTS" at 129.53,-27.034 h1.52
M6 Assembly Bottom:
  lines w0.254: -7.769,-18.474 159.921,-18.474 ; -7.719,-23.639 159.921,-23.639 ; 27.994,-28.969 27.994,-23.817 ; 43.793,-18.474 43.793,-13.31 ; 65.129,-18.474 65.129,-13.31 ; 97.31,-28.804 97.31,-13.31 ; 119.891,-28.804 159.909,-28.804 159.909,-13.31 -7.769,-13.31 -7.769,-28.804 58.194,-28.804 159.921,-28.804 159.921,-13.31
  text "COMPONENTS MARKED 'DNP' SHOULD NOT BE POPULATED." at 154.651,-8.077 h1.52
  text ".VersionControl_RevNumber" at 268.402,-9.474 h1.52
  text ".VariantName" at 128.133,-11.024 h1.52
  text "ASSEMBLY VARIANT:" at 154.524,-11.024 h1.52
  text "SVN REV:" at 38.814,-16.667 h1.52
  text ".PCB_Rev" at 52.695,-16.667 h1.52
  text "REV:" at 60.099,-16.667 h1.52
  text ".PRJ_Number" at 81.55,-16.667 h1.52
  text "BOARD #:" at 95.405,-16.667 h1.52
  text "PCB VIEWED FROM BOTTOM SIDE" at 158.308,-16.667 h1.52
  text ".TID" at 81.55,-21.831 h1.52
  text "TID #:" at 95.405,-21.831 h1.52
  text "TEXAS INSTRUMENTS" at 22.634,-27.047 h1.52
  text ".Print_Time" at 54.753,-27.047 h1.52
  text ".Print_Date" at 73.269,-27.047 h1.52
  text "GENERATED    :" at 95.355,-27.047 h1.52
  text ".plot_File_Name" at 137.849,-27.047 h1.52
  text "PLOT NAME =" at 158.308,-27.047 h1.52
M9 Title Sheet:
  drawing of 57 lines, arcs and shapes, not listed
  text "1" at 18.452,204.127 h1.78
  text "2" at 81.842,204.127 h1.78
  text "3" at 145.071,204.127 h1.78
  text "4" at 208.74,204.127 h1.78
  text "5" at 272.215,204.127 h1.78
  text "6" at 335.842,204.127 h1.78
  text "A" at -10.919,175.095 h1.78
  text "A" at 365.001,175.095 h1.78
  text "B" at -10.919,114.643 h1.78
  text "B" at 365.001,114.643 h1.78
  text "C" at -10.919,54.318 h1.78
  text "C" at 365.001,54.318 h1.78
  text "PROJECT TITLE:" at 287.785,7.048 h1.14
  text ".PRJ_Title" at 289.055,3.662 h1.78
  text "DESIGNED FOR:" at 287.785,-0.597 h1.14
  text ".PRJ_Customer" at 289.055,-4.153 h1.78
  text "D" at -10.919,-5.88 h1.78
  text "D" at 365.001,-5.88 h1.78
  text "FILE NAME:" at 287.785,-8.217 h1.14
  text ".PCB_File_Name_No_Path" at 289.055,-11.265 h1.78
  text "Texas Instruments (TI) and/or its licensors do not warrant the accuracy or completeness of this specification" at 161.56,-15.376 h1.14
  text "ENGINEER:" at 287.785,-15.583 h1.14
  text "LAYOUT BY:" at 326.012,-15.583 h1.14
  text "or any information contained therein. TI and/or its licensors do not warrant that this design will meet" at 160.417,-18.237 h1.14
  text ".PRJ_Engineer" at 289.055,-19.52 h1.78
  text ".PCB_Layout" at 327.295,-19.52 h1.78
  text "the specifications, will be suitable for your application or fit for any particular purpose, or will operate in" at 160.417,-21.099 h1.14
  text ".Layer_Name" at 14.316,-21.806 h1.52
  text "ALTIUM DESIGNER VERSION:" at 326.012,-23.457 h1.14
  text "an implementation. TI and/or its licensors do not warrant that the design is production worthy. You should" at 160.417,-23.961 h1.14
  text "completely validate and test your design implementation to confirm the system functionality for your application." at 161.56,-26.822 h1.14
  text ".print_Scale" at 289.055,-26.843 h1.78
  text ".Application_BuildNumber" at 327.295,-26.843 h1.78
  text "1" at 18.452,-32.093 h1.78
  text "2" at 81.842,-32.093 h1.78
  text "3" at 145.071,-32.093 h1.78
  text "4" at 208.74,-32.093 h1.78
  text "5" at 272.215,-32.093 h1.78
  text "6" at 335.842,-32.093 h1.78
M10 Fab Notes:
  drawing of 189 lines, arcs and shapes, not listed
  text "DESIGN INFORMATION" at 314.163,161.447 h1.52
  text "MIN. TRACK WIDTH:" at 297.791,158.091 h1.52
  text "8" at 325.636,158.091 h1.52
  text "MIL" at 329.567,158.091 h1.52
  text "7.874" at 321.41,155 h1.52
  text "MIN. CLEARANCE:" at 297.791,154.938 h1.52
  text "MIL" at 329.567,154.938 h1.52
  text "MIN. VIA PAD SIZE:" at 297.791,151.785 h1.52
  text "24" at 324.874,151.785 h1.52
  text "MIL" at 329.567,151.785 h1.52
  text "0.05mm (2MIL)" at 315.444,148.486 h1.52
  text "MINIMUM ANNULAR RING" at 289.429,148.277 h1.52
  text "EXTERNAL" at 333.428,148.277 h1.52
  text "PER" at 294.509,145.48 h1.52
  text "IPC-D-275 CLASS 2 LEVEL C" at 300.097,145.48 h1.52
  text "MIL, HOLES" at 337.898,142.928 h1.52
  text "+/-" at 327.93,142.709 h1.52
  text "+/-" at 349.621,142.709 h1.52
  text "REGISTRATION TOLERANCES:" at 289.429,142.682 h1.52
  text "METAL" at 319.903,142.682 h1.52
  text "5" at 334.539,142.683 h1.52
  text "3" at 355.697,142.683 h1.52
  text "MIL" at 358.65,142.682 h1.52
  text "HOLE SIZE TOLERANCE (UNLESS OTHERWISE SPECIFIED):" at 289.429,140.185 h1.52
  text "+/-" at 349.621,140.112 h1.52
  text "3" at 355.697,140.085 h1.52
  text "MIL" at 358.65,140.085 h1.52
  text "MATERIAL:" at 287.53,136.589 h1.52
  text "FR-4 High Tg" at 312.586,133.324 h1.52
  text "X" at 308.917,133.122 h1.52
  text "FR-4" at 298.223,133.007 h1.52
  text "OTHER" at 336.018,133.007 h1.52
  text "62 MIL (1.6mm) +/-10%" at 306.354,129.374 h1.52
  text "X" at 303.303,129.312 h1.52
  text "THICKNESS:" at 289.429,129.165 h1.52
  text "OTHER" at 338.99,129.165 h1.52
  text "TOLERANCE:" at 289.429,125.652 h1.52
  text "X" at 310.974,125.652 h1.52
  text "ANSI IPC-6012 TYPE 3 CLASS 2" at 315.496,125.652 h1.52
  text "OTHER +/-" at 315.495,121.989 h1.52
  text "BOW & TWIST:" at 289.429,118.302 h1.52
  text "X" at 310.974,118.302 h1.52
  text "ANSI IPC-6012 TYPE 3 CLASS 2" at 315.496,118.302 h1.52
  text "OTHER +/-" at 315.495,114.576 h1.52
  text "DRILLING:" at 287.53,111.258 h1.52
  text "NC_DRILL FILES" at 332.259,108.586 h1.52
  text "REFERENCE:" at 289.429,108.486 h1.52
  text "X" at 306.123,108.484 h1.52
  text "AS SHOWN" at 310.644,108.486 h1.52
  text "X" at 329.008,108.486 h1.52
  text "OTHER" at 339.828,104.873 h1.52
  text "PTH COPPER THICKNESS:" at 289.421,104.783 h1.52
  text "X" at 318.357,104.783 h1.52
  text "20-30 um" at 321.608,104.783 h1.52
  text "BOARD FINISH:" at 287.53,101.034 h1.52
  text "SILKSCREEN:" at 291.473,98.237 h1.52
  text "X" at 315.8,98.237 h1.52
  text "TOP" at 318.772,98.237 h1.52
  text "X" at 328.754,98.237 h1.52
  text "BOTTOM" at 331.751,98.237 h1.52
  text "SILKSCREEN COLOR:" at 291.473,94.295 h1.52
  text "X" at 315.775,94.295 h1.52
  text "WHITE" at 318.772,94.295 h1.52
  text "OTHER" at 331.751,94.295 h1.52
  text "X" at 319.102,90.652 h1.52
  text "GREEN" at 322.099,90.652 h1.52
  text "OTHER" at 337.796,90.652 h1.52
  text "SOLDER RESIST COLOR:" at 291.473,90.477 h1.52
  text "X" at 319.102,86.734 h1.52
  text "MATTE" at 322.099,86.734 h1.52
  text "SEMI-GLOSS" at 337.785,86.717 h1.52
  text "IMMERSION GOLD (ENIG)" at 314.479,82.345 h1.52
  text "ENEPIG" at 348.453,82.162 h1.52
  text "SURFACE FINISH:" at 287.53,82.136 h1.52
  text "X" at 309.958,82.136 h1.52
  text "IMM. TIN/SILVER OR EQUIV" at 295.9,78.649 h1.52
  text "OTHER" at 332.259,78.549 h1.52
  text "ARRAY/PANEL:" at 287.53,74.602 h1.52
  text "CUT AND TRIM PER M1 BOARD OUTLINE" at 314.479,74.393 h1.52
  text "N.C. ROUTE" at 314.479,70.94 h1.52
  text "X" at 331.955,70.94 h1.52
  text "V. SCORE" at 336.476,70.94 h1.52
  text "CERTIFICATION:" at 287.53,67.66 h1.52
  text "MATERIALS AND WORKMANSHIP FOR ALL PCBS" at 305.945,67.66 h1.52
  text "TO MEET OR EXCEED THE REQUIREMENTS OF:" at 305.945,65.271 h1.52
  text "X" at 296.738,62.003 h1.52
  text "ANSI IPC-A-600F CLASS ->" at 299.989,62.003 h1.52
  text "X" at 341.848,62.003 h1.52
  text "2" at 344.642,62.003 h1.52
  text "1" at 336.641,61.965 h1.52
  text "3" at 353.633,61.965 h1.52
  text "X" at 317.362,58.252 h1.52
  text "RoHS" at 320.613,58.252 h1.52
  text "OTHER" at 336.981,58.252 h1.52
  text "PER ORDER" at 347.067,58.252 h1.52
  text "ALL BOARDS MUST MEET OR EXCEED UL94-V0 REQUIREMENTS." at 288.229,54.345 h1.52
  text "PCB MUST BEAR THE UL94V-0 UL REGISTERED MATERIAL ID NUMBER" at 288.229,51.397 h1.52
  text "ADDITIONAL REQUIREMENTS:" at 287.53,47.094 h1.52
  text "MICROSECTION:" at 289.429,44.373 h1.52
  text "YES" at 312.435,44.373 h1.52
  text "REQUIRED" at 334.317,40.707 h1.52
  text "BARE BOARD ELEC. TEST:" at 289.429,40.634 h1.52
  text "NONE" at 322.595,40.634 h1.52
  text "X" at 331.32,40.634 h1.52
  text "PER ORDER" at 349.353,40.634 h1.52
  text "XX MIL VIAS REQUIRE NON-CONDUCTIVE FILL AND PLANARIZE" at 293.7,35.428 h1.5
  text "XX MIL VIAS REQUIRE CONDUCTIVE FILL AND PLANARIZE" at 293.903,32.787 h1.52
  text "OUTER XX MIL TRACES REQUIRE 50 OHM SINGLE-ENDED IMPEDANCE" at 293.878,28.637 h1.47
  text "LAYER 2 & 3 (INNER LAYERS) XX MIL WIDE, XX MIL SPACE / TRACES REQUIRE 100 OHM DIFFERENTIAL IMPEDANCE" at 293.675,22.65 h1.52
  text ".Layer_Name" at 14.316,-21.806 h1.52
M11 Gerber Information:
  lines w0.254: -7.757,-23.626 159.883,-23.626 ; -7.757,-18.462 159.934,-18.462 ; -7.757,-13.297 -7.757,-28.791 93.97,-28.791 159.934,-28.791 159.934,-13.297 -7.744,-13.297 -7.744,-28.791 32.274,-28.791 ; 54.854,-28.791 54.854,-13.297 ; 87.036,-18.462 87.036,-13.297 ; 108.372,-18.462 108.372,-13.297 ; 124.171,-28.956 124.171,-23.804
  text "ALL ARTWORK VIEWED FROM TOP SIDE" at -6.144,-16.654 h1.52
  text "BOARD #:" at 56.759,-16.654 h1.52
  text ".PRJ_Number" at 70.615,-16.654 h1.52
  text "REV:" at 92.065,-16.654 h1.52
  text ".PCB_Rev" at 99.469,-16.654 h1.52
  text "SVN REV:" at 113.35,-16.654 h1.52
  text ".VersionControl_RevNumber" at 126.203,-16.654 h1.52
  text "LAYER NAME =" at -6.144,-21.806 h1.52
  text "TID #:" at 56.759,-21.819 h1.52
  text ".TID" at 70.615,-21.819 h1.52
  text "PLOT NAME =" at -6.144,-27.034 h1.52
  text ".plot_File_Name" at 14.316,-27.034 h1.52
  text "GENERATED    :" at 56.81,-27.034 h1.52
  text ".Print_Date" at 78.895,-27.034 h1.52
  text ".Print_Time" at 97.412,-27.034 h1.52
  text "TEXAS INSTRUMENTS" at 129.53,-27.034 h1.52
M12 Stackup:
  drawing of 295 lines, arcs and shapes, not listed
  text "Layer" at 20.309,155.27 h1.52
  text "Name" at 30.721,155.27 h1.52
  text "Material" at 54.337,155.27 h1.52
  text "Thickness" at 76.175,155.27 h1.52
  text "Constant" at 92.68,155.27 h1.52
  text "Board Layer Stack" at 107.155,155.27 h1.52
  text "Top Overlay" at 30.721,152.222 h1.52
  text "Top Solder" at 30.721,149.174 h1.52
  text "Solder Resist" at 54.337,149.174 h1.52
  text "0.40mil" at 76.175,149.174 h1.52
  text "3.5" at 92.68,149.174 h1.52
  text "1" at 20.309,146.126 h1.52
  text "Top Layer" at 30.721,146.126 h1.52
  text "2.76mil" at 76.175,146.126 h1.52
  text "Dielectric1" at 30.721,143.078 h1.52
  text "FR-4 High Tg" at 54.337,143.078 h1.52
  text "59.20mil" at 76.175,143.078 h1.52
  text "4.8" at 92.68,143.078 h1.52
  text "2" at 20.309,140.03 h1.52
  text "Mid-Layer 1" at 30.721,140.03 h1.52
  text "1.40mil" at 76.175,140.03 h1.52
  text "Dielectric2" at 30.721,136.982 h1.52
  text "FR-4" at 54.337,136.982 h1.52
  text "12.60mil" at 76.175,136.982 h1.52
  text "4.8" at 92.68,136.982 h1.52
  text "3" at 20.309,133.934 h1.52
  text "Mid-Layer 2" at 30.721,133.934 h1.52
  text "1.40mil" at 76.175,133.934 h1.52
  text "Dielectric3" at 30.721,130.886 h1.52
  text "FR-4" at 54.337,130.886 h1.52
  text "12.60mil" at 76.175,130.886 h1.52
  text "4.8" at 92.68,130.886 h1.52
  text "4" at 20.309,127.838 h1.52
  text "Bottom Layer" at 30.721,127.838 h1.52
  text "2.76mil" at 76.175,127.838 h1.52
  text "Bottom Solder" at 30.721,124.79 h1.52
  text "Solder Resist" at 54.337,124.79 h1.52
  text "0.40mil" at 76.175,124.79 h1.52
  text "3.5" at 92.68,124.79 h1.52
  text "Bottom Overlay" at 30.721,121.742 h1.52
  text ".Layer_Name" at 14.316,-21.806 h1.52
M13 Component Bodies Top:
  text ".Layer_Name" at 14.316,-21.806 h1.52
M14 Component Bodies Bottom:
  text ".Layer_Name" at 14.316,-21.806 h1.52
M15 Courtyards Top:
  text ".Layer_Name" at 14.316,-21.806 h1.52
M16 Courtyards Bottom:
  text ".Layer_Name" at 14.316,-21.806 h1.52
Drill Drawing:
  drawing of 177 lines, arcs and shapes, not listed
  text "Symbol" at 190.623,105.699 h1.83
  text "Count" at 198.257,105.699 h1.83
  text "Hole Size" at 205.919,105.699 h1.83
  text "Plated" at 220.194,105.699 h1.83
  text "Hole Type" at 226.776,105.699 h1.83
  text "Drill Layer Pair" at 236.305,105.699 h1.83
  text "Hole Tolerance" at 254.703,105.699 h1.83
  text "55" at 198.257,102.541 h1.52
  text "0.200mm (7.87mil)" at 205.919,102.541 h1.52
  text "PTH" at 220.194,102.541 h1.52
  text "Round" at 226.776,102.541 h1.52
  text "Top Layer - Bottom Layer" at 236.305,102.541 h1.52
  text "51" at 198.257,99.384 h1.52
  text "0.203mm (8.00mil)" at 205.919,99.384 h1.52
  text "PTH" at 220.194,99.384 h1.52
  text "Round" at 226.776,99.384 h1.52
  text "Top Layer - Bottom Layer" at 236.305,99.384 h1.52
  text "4" at 198.257,96.226 h1.52
  text "0.300mm (11.81mil)" at 205.919,96.226 h1.52
  text "PTH" at 220.194,96.226 h1.52
  text "Round" at 226.776,96.226 h1.52
  text "Top Layer - Bottom Layer" at 236.305,96.226 h1.52
  text "H" at 189.981,95.972 h1.4
  text "9" at 198.257,93.068 h1.52
  text "0.305mm (12.00mil)" at 205.919,93.068 h1.52
  text "PTH" at 220.194,93.068 h1.52
  text "Round" at 226.776,93.068 h1.52
  text "Top Layer - Bottom Layer" at 236.305,93.068 h1.52
  text "26" at 198.257,89.91 h1.52
  text "0.356mm (14.00mil)" at 205.919,89.91 h1.52
  text "PTH" at 220.194,89.91 h1.52
  text "Round" at 226.776,89.91 h1.52
  text "Top Layer - Bottom Layer" at 236.305,89.91 h1.52
  text "10" at 198.257,86.753 h1.52
  text "0.381mm (15.00mil)" at 205.919,86.753 h1.52
  text "PTH" at 220.194,86.753 h1.52
  text "Round" at 226.776,86.753 h1.52
  text "Top Layer - Bottom Layer" at 236.305,86.753 h1.52
  text "C" at 189.981,86.499 h1.4
  text "2" at 198.257,83.595 h1.52
  text "0.400mm (15.75mil)" at 205.919,83.595 h1.52
  text "PTH" at 220.194,83.595 h1.52
  text "Round" at 226.776,83.595 h1.52
  text "Top Layer - Bottom Layer" at 236.305,83.595 h1.52
  text "B" at 189.981,83.341 h1.4
  text "65" at 198.257,80.437 h1.52
  text "0.406mm (16.00mil)" at 205.919,80.437 h1.52
  text "PTH" at 220.194,80.437 h1.52
  text "Round" at 226.776,80.437 h1.52
  text "Top Layer - Bottom Layer" at 236.305,80.437 h1.52
  text "2" at 198.257,77.28 h1.52
  text "0.465mm (18.29mil)" at 205.919,77.28 h1.52
  text "PTH" at 220.194,77.28 h1.52
  text "Round" at 226.776,77.28 h1.52
  text "Top Layer - Bottom Layer" at 236.305,77.28 h1.52
  text "2" at 198.257,74.122 h1.52
  text "0.650mm (25.59mil)" at 205.919,74.122 h1.52
  text "NPTH" at 220.194,74.122 h1.52
  text "Round" at 226.776,74.122 h1.52
  text "Top Layer - Bottom Layer" at 236.305,74.122 h1.52
  text "12" at 198.257,70.964 h1.52
  text "0.650mm (25.59mil)" at 205.919,70.964 h1.52
  text "PTH" at 220.194,70.964 h1.52
  text "Round" at 226.776,70.964 h1.52
  text "Top Layer - Bottom Layer" at 236.305,70.964 h1.52
  text "G" at 189.981,70.71 h1.4
  text "4" at 198.257,67.806 h1.52
  text "0.900mm (35.43mil)" at 205.919,67.806 h1.52
  text "PTH" at 220.194,67.806 h1.52
  text "Round" at 226.776,67.806 h1.52
  text "Top Layer - Bottom Layer" at 236.305,67.806 h1.52
  text "1" at 198.257,64.649 h1.52
  text "1.016mm (40.00mil)" at 205.919,64.649 h1.52
  text "PTH" at 220.194,64.649 h1.52
  text "Round" at 226.776,64.649 h1.52
  text "Top Layer - Bottom Layer" at 236.305,64.649 h1.52
  text "42" at 198.257,61.491 h1.52
  text "1.100mm (43.31mil)" at 205.919,61.491 h1.52
  text "PTH" at 220.194,61.491 h1.52
  text "Round" at 226.776,61.491 h1.52
  text "Top Layer - Bottom Layer" at 236.305,61.491 h1.52
  text "F" at 189.981,61.237 h1.4
  text "22" at 198.257,58.333 h1.52
  text "1.150mm (45.28mil)" at 205.919,58.333 h1.52
  text "PTH" at 220.194,58.333 h1.52
  text "Round" at 226.776,58.333 h1.52
  text "Top Layer - Bottom Layer" at 236.305,58.333 h1.52
  text "4" at 198.257,55.175 h1.52
  text "1.300mm (51.18mil)" at 205.919,55.175 h1.52
  text "PTH" at 220.194,55.175 h1.52
  text "Round" at 226.776,55.175 h1.52
  text "Top Layer - Bottom Layer" at 236.305,55.175 h1.52
  text "2" at 198.257,52.018 h1.52
  text "1.400mm (55.12mil)" at 205.919,52.018 h1.52
  text "PTH" at 220.194,52.018 h1.52
  text "Slot" at 226.776,52.018 h1.52
  text "Top Layer - Bottom Layer" at 236.305,52.018 h1.52
  text "D" at 189.981,51.764 h1.4
  text "10" at 198.257,48.86 h1.52
  text "1.500mm (59.06mil)" at 205.919,48.86 h1.52
  text "PTH" at 220.194,48.86 h1.52
  text "Round" at 226.776,48.86 h1.52
  text "Top Layer - Bottom Layer" at 236.305,48.86 h1.52
  text "17" at 198.257,45.702 h1.52
  text "1.600mm (63.00mil)" at 205.919,45.702 h1.52
  text "PTH" at 220.194,45.702 h1.52
  text "Round" at 226.776,45.702 h1.52
  text "Top Layer - Bottom Layer" at 236.305,45.702 h1.52
  text "2" at 198.257,42.545 h1.52
  text "1.700mm (66.93mil)" at 205.919,42.545 h1.52
  text "PTH" at 220.194,42.545 h1.52
  text "Slot" at 226.776,42.545 h1.52
  text "Top Layer - Bottom Layer" at 236.305,42.545 h1.52
  text "E" at 189.981,42.291 h1.4
  text "342 Total" at 198.257,39.387 h1.52
  text "Slot definitions :" at 190.623,37.176 h1.52
  text "Routed Path Length" at 202.071,37.176 h1.52
  text "= Calculated from tool start centre position to tool end centre position." at 215.78,37.176 h1.52
  text "Hole Length" at 202.071,35.913 h1.52
  text "= Routed Path Length + Tool Size = Slot length as defined in the PCB layout" at 210.705,35.913 h1.52
  text ".Layer_Name" at 14.316,-21.806 h1.52
M17 Embedded Cavity:
  text ".Layer_Name" at 14.316,-21.806 h1.52
M18 Embedded Assembly:
  text ".Layer_Name" at 14.316,-21.806 h1.52
M19 Embedded Keepout:
  text ".Layer_Name" at 14.316,-21.806 h1.52

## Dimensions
-0.34,-10.16 to 25.06,-10.16 on M2 Board Dimensions
-0.34,0 to -0.051,71.99 on M2 Board Dimensions
-0.34,0 to 0,17.163 on M2 Board Dimensions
